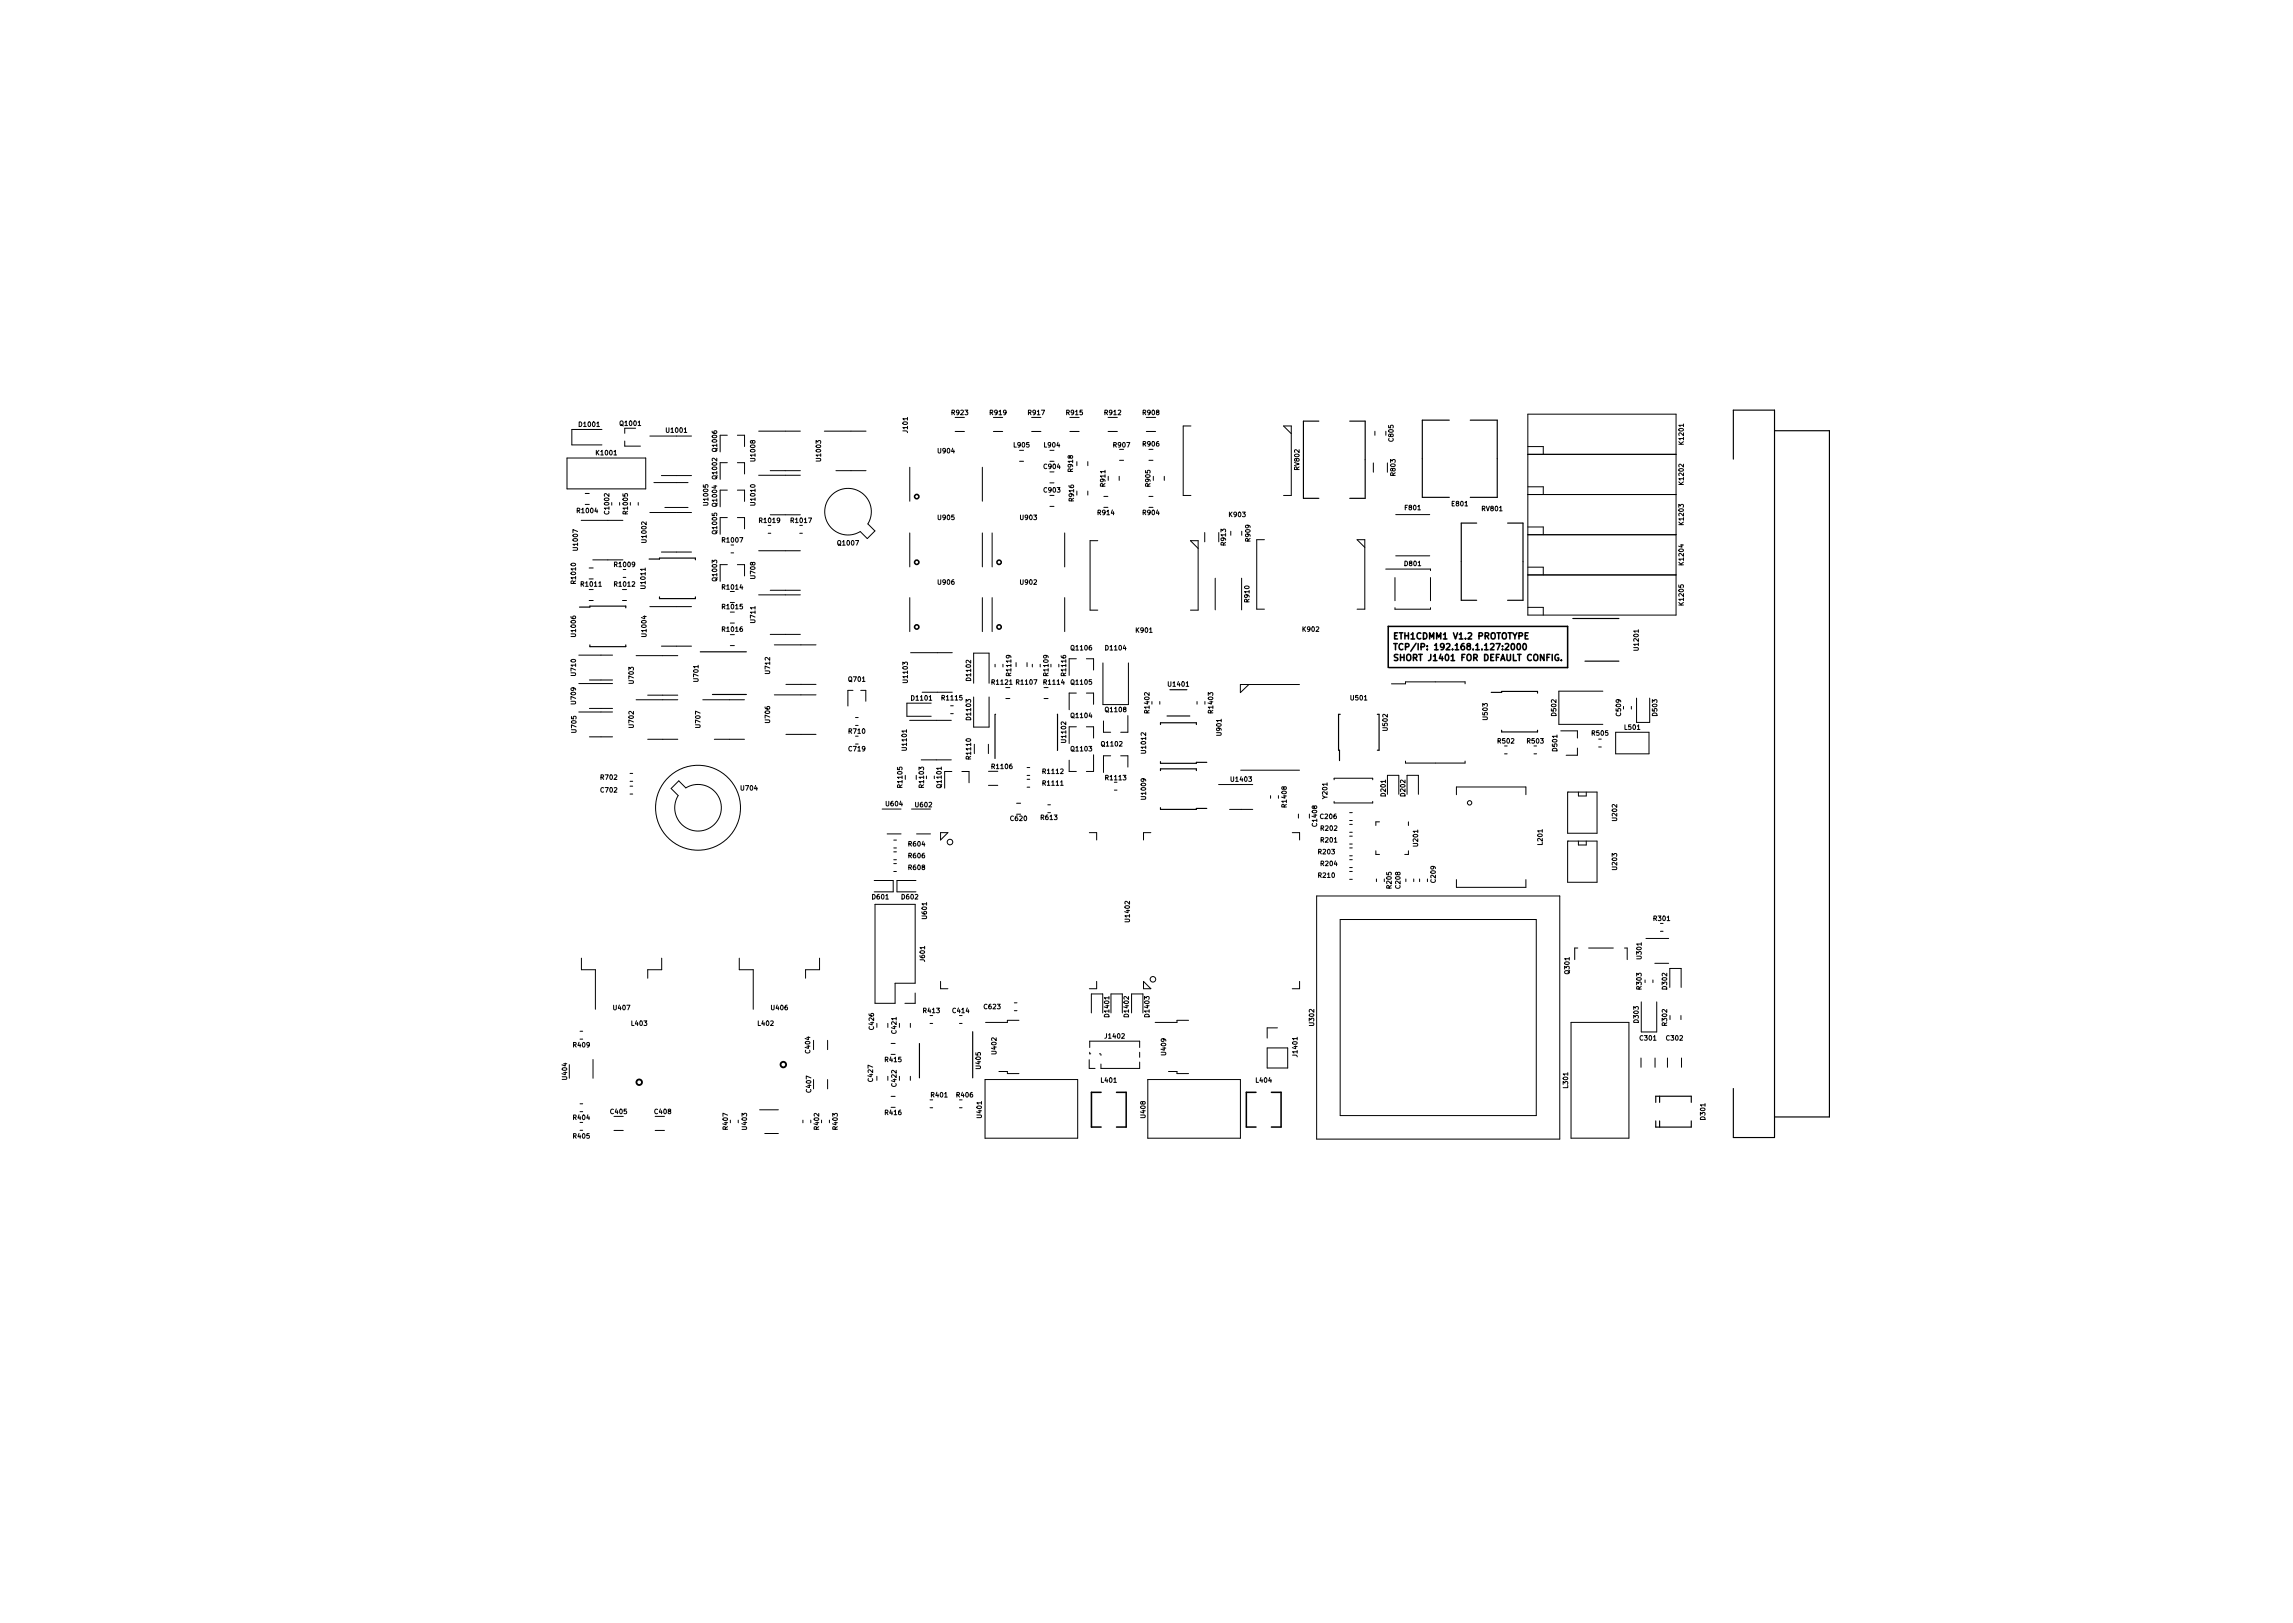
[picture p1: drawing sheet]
<svg xmlns="http://www.w3.org/2000/svg" width="297mm" height="210mm" viewBox="0 0 297 210" stroke-linecap="round" stroke-linejoin="round" font-family="sans-serif">
<defs><g id="words">
<g font-size="1.1">
<text x="180.3" y="82.8">ETH1CDMM1 V1.2 PROTOTYPE</text>
<text x="180.3" y="84.2">TCP/IP: 192.168.1.127:2000</text>
<text x="180.3" y="85.6">SHORT J1401 FOR DEFAULT CONFIG.</text>
</g>
<g font-size=".8">
<text x="123.3" y="53.8">R923</text>
<text x="128.3" y="53.8">R919</text>
<text x="133.2" y="53.8">R917</text>
<text x="138.2" y="53.8">R915</text>
<text x="143.1" y="53.8">R912</text>
<text x="148.1" y="53.8">R908</text>
<text x="75.1" y="55.3">D1001</text>
<text x="77.3" y="59">K1001</text>
<text x="80.4" y="55.2">Q1001</text>
<text x="86.4" y="56">U1001</text>
<text x="92.9" y="58.4" transform="rotate(-90 92.9 58.4)">Q1006</text>
<text x="97.8" y="59.6" transform="rotate(-90 97.8 59.6)">U1008</text>
<text x="106.3" y="59.6" transform="rotate(-90 106.3 59.6)">U1003</text>
<text x="117.6" y="56" transform="rotate(-90 117.6 56)">J101</text>
<text x="121.6" y="58.7">U904</text>
<text x="131.4" y="58">L905</text>
<text x="135.3" y="58">L904</text>
<text x="144.3" y="58">R907</text>
<text x="148.1" y="57.8">R906</text>
<text x="180.5" y="57.1" transform="rotate(-90 180.5 57.1)">C805</text>
<text x="218.1" y="57.5" transform="rotate(-90 218.1 57.5)">K1201</text>
<text x="91.7" y="65.4" transform="rotate(-90 91.7 65.4)">U1005</text>
<text x="92.9" y="65.5" transform="rotate(-90 92.9 65.5)">Q1004</text>
<text x="92.9" y="62" transform="rotate(-90 92.9 62)">Q1002</text>
<text x="97.8" y="65.4" transform="rotate(-90 97.8 65.4)">U1010</text>
<text x="135.3" y="60.7">C904</text>
<text x="135.3" y="63.8">C903</text>
<text x="139" y="61.1" transform="rotate(-90 139 61.1)">R918</text>
<text x="139.1" y="64.9" transform="rotate(-90 139.1 64.9)">R916</text>
<text x="143.2" y="63" transform="rotate(-90 143.2 63)">R911</text>
<text x="149" y="63" transform="rotate(-90 149 63)">R905</text>
<text x="168.3" y="60.8" transform="rotate(-90 168.3 60.8)">RV802</text>
<text x="180.8" y="61.6" transform="rotate(-90 180.8 61.6)">R803</text>
<text x="188.1" y="65.6">E801</text>
<text x="218.1" y="62.7" transform="rotate(-90 218.1 62.7)">K1202</text>
<text x="74.8" y="66.5">R1004</text>
<text x="74.8" y="71.2" transform="rotate(-90 74.8 71.2)">U1007</text>
<text x="78.9" y="66.5" transform="rotate(-90 78.9 66.5)">C1002</text>
<text x="81.3" y="66.5" transform="rotate(-90 81.3 66.5)">R1005</text>
<text x="83.7" y="70.2" transform="rotate(-90 83.7 70.2)">U1002</text>
<text x="92.9" y="69.1" transform="rotate(-90 92.9 69.1)">Q1005</text>
<text x="93.6" y="70.3">R1007</text>
<text x="98.5" y="67.7">R1019</text>
<text x="102.5" y="67.7">R1017</text>
<text x="108.6" y="70.7">Q1007</text>
<text x="121.6" y="67.4">U905</text>
<text x="132.2" y="67.4">U903</text>
<text x="142.3" y="66.7">R914</text>
<text x="148.1" y="66.7">R904</text>
<text x="158.8" y="70.6" transform="rotate(-90 158.8 70.6)">R913</text>
<text x="159.3" y="67">K903</text>
<text x="162" y="70.1" transform="rotate(-90 162 70.1)">R909</text>
<text x="182.1" y="66.1">F801</text>
<text x="192" y="66.2">RV801</text>
<text x="218.1" y="67.9" transform="rotate(-90 218.1 67.9)">K1203</text>
<text x="74.6" y="75.5" transform="rotate(-90 74.6 75.5)">R1010</text>
<text x="75.4" y="76">R1011</text>
<text x="79.7" y="76">R1012</text>
<text x="79.7" y="73.4">R1009</text>
<text x="83.6" y="76.2" transform="rotate(-90 83.6 76.2)">U1011</text>
<text x="92.9" y="75.2" transform="rotate(-90 92.9 75.2)">Q1003</text>
<text x="93.6" y="76.4">R1014</text>
<text x="97.8" y="74.9" transform="rotate(-90 97.8 74.9)">U708</text>
<text x="121.6" y="75.7">U906</text>
<text x="132.2" y="75.7">U902</text>
<text x="161.8" y="78" transform="rotate(-90 161.8 78)">R910</text>
<text x="182" y="73.3">D801</text>
<text x="218.1" y="73.1" transform="rotate(-90 218.1 73.1)">K1204</text>
<text x="74.6" y="82.4" transform="rotate(-90 74.6 82.4)">U1006</text>
<text x="83.7" y="82.4" transform="rotate(-90 83.7 82.4)">U1004</text>
<text x="93.6" y="81.8">R1016</text>
<text x="93.6" y="78.9">R1015</text>
<text x="97.8" y="80.6" transform="rotate(-90 97.8 80.6)">U711</text>
<text x="147.2" y="82">K901</text>
<text x="168.8" y="81.8">K902</text>
<text x="218.1" y="78.3" transform="rotate(-90 218.1 78.3)">K1205</text>
<text x="74.6" y="87.5" transform="rotate(-90 74.6 87.5)">U710</text>
<text x="82.1" y="88.5" transform="rotate(-90 82.1 88.5)">U703</text>
<text x="90.5" y="88.2" transform="rotate(-90 90.5 88.2)">U701</text>
<text x="99.7" y="87.2" transform="rotate(-90 99.7 87.2)">U712</text>
<text x="110" y="88.3">Q701</text>
<text x="117.6" y="88.3" transform="rotate(-90 117.6 88.3)">U1103</text>
<text x="125.8" y="88.1" transform="rotate(-90 125.8 88.1)">D1102</text>
<text x="128.6" y="88.7">R1121</text>
<text x="131" y="87.5" transform="rotate(-90 131 87.5)">R1119</text>
<text x="131.7" y="88.7">R1107</text>
<text x="135.3" y="88.7">R1114</text>
<text x="135.8" y="87.5" transform="rotate(-90 135.8 87.5)">R1109</text>
<text x="138.1" y="87.5" transform="rotate(-90 138.1 87.5)">R1116</text>
<text x="138.8" y="84.2">Q1106</text>
<text x="138.8" y="88.7">Q1105</text>
<text x="143.3" y="84.2">D1104</text>
<text x="151.4" y="88.9">U1401</text>
<text x="212.3" y="84.2" transform="rotate(-90 212.3 84.2)">U1201</text>
<text x="74.6" y="91.2" transform="rotate(-90 74.6 91.2)">U709</text>
<text x="74.7" y="94.8" transform="rotate(-90 74.7 94.8)">U705</text>
<text x="82.1" y="94.2" transform="rotate(-90 82.1 94.2)">U702</text>
<text x="90.7" y="94.2" transform="rotate(-90 90.7 94.2)">U707</text>
<text x="99.7" y="93.6" transform="rotate(-90 99.7 93.6)">U706</text>
<text x="110" y="95">R710</text>
<text x="118.1" y="90.7">D1101</text>
<text x="122.1" y="90.7">R1115</text>
<text x="125.8" y="93.2" transform="rotate(-90 125.8 93.2)">D1103</text>
<text x="138.8" y="93">Q1104</text>
<text x="143.3" y="92.2">Q1108</text>
<text x="148.9" y="92.3" transform="rotate(-90 148.9 92.3)">R1402</text>
<text x="157.1" y="92.3" transform="rotate(-90 157.1 92.3)">R1403</text>
<text x="158.2" y="95.2" transform="rotate(-90 158.2 95.2)">U901</text>
<text x="175" y="90.7">U501</text>
<text x="179.8" y="94.6" transform="rotate(-90 179.8 94.6)">U502</text>
<text x="192.7" y="93.2" transform="rotate(-90 192.7 93.2)">U503</text>
<text x="201.6" y="92.7" transform="rotate(-90 201.6 92.7)">D502</text>
<text x="206.3" y="95.3">R505</text>
<text x="210" y="92.7" transform="rotate(-90 210 92.7)">C509</text>
<text x="210.5" y="94.5">L501</text>
<text x="214.7" y="92.7" transform="rotate(-90 214.7 92.7)">D503</text>
<text x="77.9" y="101">R702</text>
<text x="110" y="97.3">C719</text>
<text x="116.9" y="101.9" transform="rotate(-90 116.9 101.9)">R1105</text>
<text x="117.5" y="97.1" transform="rotate(-90 117.5 97.1)">U1101</text>
<text x="119.7" y="101.9" transform="rotate(-90 119.7 101.9)">R1103</text>
<text x="122" y="102" transform="rotate(-90 122 102)">Q1101</text>
<text x="125.8" y="98.3" transform="rotate(-90 125.8 98.3)">R1110</text>
<text x="128.6" y="99.6">R1106</text>
<text x="135.2" y="100.2">R1112</text>
<text x="135.2" y="101.8">R1111</text>
<text x="138.1" y="96.1" transform="rotate(-90 138.1 96.1)">U1102</text>
<text x="138.8" y="97.3">Q1103</text>
<text x="142.8" y="96.7">Q1102</text>
<text x="143.3" y="101.1">R1113</text>
<text x="148.4" y="97.5" transform="rotate(-90 148.4 97.5)">U1012</text>
<text x="159.6" y="101.3">U1403</text>
<text x="194.1" y="96.3">R502</text>
<text x="197.9" y="96.3">R503</text>
<text x="201.7" y="97.3" transform="rotate(-90 201.7 97.3)">D501</text>
<text x="77.9" y="102.7">C702</text>
<text x="96" y="102.4">U704</text>
<text x="114.8" y="104.4">U604</text>
<text x="118.6" y="104.6">U602</text>
<text x="131" y="106.3">C620</text>
<text x="134.9" y="106.2">R613</text>
<text x="148.4" y="103.5" transform="rotate(-90 148.4 103.5)">U1009</text>
<text x="166.7" y="104.5" transform="rotate(-90 166.7 104.5)">R1408</text>
<text x="170.6" y="107" transform="rotate(-90 170.6 107)">C1408</text>
<text x="171.1" y="106.1">C206</text>
<text x="171.1" y="107.6">R202</text>
<text x="171.9" y="103.4" transform="rotate(-90 171.9 103.4)">Y201</text>
<text x="179.5" y="103.1" transform="rotate(-90 179.5 103.1)">D201</text>
<text x="182" y="103.1" transform="rotate(-90 182 103.1)">D202</text>
<text x="209.5" y="106.3" transform="rotate(-90 209.5 106.3)">U202</text>
<text x="117.7" y="112.7">R608</text>
<text x="117.7" y="111.2">R606</text>
<text x="117.7" y="109.6">R604</text>
<text x="170.8" y="113.7">R210</text>
<text x="170.8" y="110.7">R203</text>
<text x="171.1" y="112.2">R204</text>
<text x="171.1" y="109.1">R201</text>
<text x="183.7" y="109.6" transform="rotate(-90 183.7 109.6)">U201</text>
<text x="199.8" y="109.4" transform="rotate(-90 199.8 109.4)">L201</text>
<text x="209.5" y="112.6" transform="rotate(-90 209.5 112.6)">U203</text>
<text x="113" y="116.5">D601</text>
<text x="116.9" y="116.5">D602</text>
<text x="120.1" y="119" transform="rotate(-90 120.1 119)">U601</text>
<text x="146.3" y="119.3" transform="rotate(-90 146.3 119.3)">U1402</text>
<text x="180.3" y="115" transform="rotate(-90 180.3 115)">R205</text>
<text x="181.4" y="115" transform="rotate(-90 181.4 115)">C208</text>
<text x="186" y="114.3" transform="rotate(-90 186 114.3)">C209</text>
<text x="214.3" y="119.3">R301</text>
<text x="119.8" y="124.5" transform="rotate(-90 119.8 124.5)">J601</text>
<text x="212.6" y="124.2" transform="rotate(-90 212.6 124.2)">U301</text>
<text x="79.5" y="130.9">U407</text>
<text x="100" y="130.9">U406</text>
<text x="119.7" y="131.2">R413</text>
<text x="123.5" y="131.2">C414</text>
<text x="127.5" y="130.7">C623</text>
<text x="143.7" y="131.7" transform="rotate(-90 143.7 131.7)">D1401</text>
<text x="146.2" y="131.7" transform="rotate(-90 146.2 131.7)">D1402</text>
<text x="148.9" y="131.7" transform="rotate(-90 148.9 131.7)">D1403</text>
<text x="203.3" y="126.1" transform="rotate(-90 203.3 126.1)">Q301</text>
<text x="212.6" y="128.1" transform="rotate(-90 212.6 128.1)">R303</text>
<text x="215.9" y="128.1" transform="rotate(-90 215.9 128.1)">D302</text>
<text x="74.3" y="135.7">R409</text>
<text x="81.9" y="132.9">L403</text>
<text x="98.2" y="132.9">L402</text>
<text x="104.9" y="136.4" transform="rotate(-90 104.9 136.4)">C404</text>
<text x="113.2" y="133.3" transform="rotate(-90 113.2 133.3)">C426</text>
<text x="114.7" y="137.6">R415</text>
<text x="116.1" y="133.8" transform="rotate(-90 116.1 133.8)">C421</text>
<text x="129.1" y="136.5" transform="rotate(-90 129.1 136.5)">U402</text>
<text x="143.2" y="134.5">J1402</text>
<text x="151" y="136.6" transform="rotate(-90 151 136.6)">U409</text>
<text x="168.1" y="136.8" transform="rotate(-90 168.1 136.8)">J1401</text>
<text x="170.2" y="132.8" transform="rotate(-90 170.2 132.8)">U302</text>
<text x="212.3" y="132.4" transform="rotate(-90 212.3 132.4)">D303</text>
<text x="212.5" y="134.8">C301</text>
<text x="215.9" y="134.8">C302</text>
<text x="215.9" y="132.8" transform="rotate(-90 215.9 132.8)">R302</text>
<text x="73.5" y="139.8" transform="rotate(-90 73.5 139.8)">U404</text>
<text x="105.1" y="141.5" transform="rotate(-90 105.1 141.5)">C407</text>
<text x="113.1" y="140.1" transform="rotate(-90 113.1 140.1)">C427</text>
<text x="116.1" y="140.7" transform="rotate(-90 116.1 140.7)">C422</text>
<text x="120.7" y="142.2">R401</text>
<text x="124" y="142.2">R406</text>
<text x="127" y="138.4" transform="rotate(-90 127 138.4)">U405</text>
<text x="142.7" y="140.2">L401</text>
<text x="162.8" y="140.2">L404</text>
<text x="203.1" y="140.9" transform="rotate(-90 203.1 140.9)">L301</text>
<text x="74.3" y="147.5">R405</text>
<text x="74.3" y="145.1">R404</text>
<text x="79.1" y="144.3">C405</text>
<text x="84.9" y="144.3">C408</text>
<text x="94.3" y="146.3" transform="rotate(-90 94.3 146.3)">R407</text>
<text x="96.8" y="146.3" transform="rotate(-90 96.8 146.3)">U403</text>
<text x="106.1" y="146.3" transform="rotate(-90 106.1 146.3)">R402</text>
<text x="108.5" y="146.3" transform="rotate(-90 108.5 146.3)">R403</text>
<text x="114.7" y="144.4">R416</text>
<text x="127.2" y="144.8" transform="rotate(-90 127.2 144.8)">U401</text>
<text x="148.4" y="144.8" transform="rotate(-90 148.4 144.8)">U408</text>
<text x="220.9" y="145" transform="rotate(-90 220.9 145)">D301</text>
</g>
</g></defs>
<g fill="none" stroke="#000" stroke-width=".2">
<path d="M179.8 86.5v-5.4h23.3v5.4h-23.1M195 83.5l.3-.1 .1 .2-.5 .6h.5M195.8 83.5l.1-.1a.43 .43 0 0 1 .3 .4 .43 .43 0 0 1-.3 .4l-.2-.3zM196.6 83.5l.1-.1a.43 .43 0 0 1 .3 .4 .43 .43 0 0 1-.3 .4l-.2-.3zM197.4 83.4h.1a.43 .43 0 0 1 .2 .4 .43 .43 0 0 1-.2 .4 .53 .53 0 0 1-.1-.8zM197.6 82.4h.2M198 82h-.4v.8h.4M201.9 84.8a.36 .36 0 0 0-.5 .4 .36 .36 0 0 0 .5 .3v-.3h-.1M202.3 85.5v.1M142.6 141.5h-1.2v4.5h1.2M144.6 141.5h1.3v4.5h-1.3M162.7 141.5h-1.2v4.5h1.2"/>
<path d="M164.7 141.5h1.3v4.5h-1.3"/>
<circle cx="118.8" cy="64.3" r=".28"/>
<circle cx="118.8" cy="72.8" r=".28"/>
<circle cx="129.4" cy="72.8" r=".28"/>
<circle cx="118.8" cy="81.2" r=".28"/>
<circle cx="129.4" cy="81.2" r=".28"/>
</g>
<g fill="none" stroke="#000" stroke-width=".13">
<path d="M73.4 59.3h10.2v4h-10.2zM78 55.6h-3.9v2h3.9M80.9 57.1v.7h2.1M82.3 55.5h-1.4v.6M84.2 56.5h5.4M94.2 56.4h-.9v2.1M94.2 59.9h-.9v2.2M95.5 56.4h.9v1.4M95.5 59.9h.9v1.5M98.3 55.9h5.4M106.8 55.9h5.4M123.7 54.1h1.2"/>
<path d="M123.7 55.9h1.2M128.7 54.1h1.2M128.7 55.9h1.2M132.1 58.3h.5M132.1 59.8h.5M133.6 54.1h1.2M133.6 55.9h1.2M136 58.3h.5M136 59.8h.5M138.6 54.1h1.2M138.6 55.9h1.2M139.5 59.8v.5"/>
<path d="M140.9 59.8v.5M143.5 54.1h1.2M143.5 55.9h1.2M145 59.6h.5M148.5 54.1h1.2M148.5 55.9h1.2M148.8 59.6h.6M148.8 58.2h.6M154.3 55.2h-1v9h1M167.3 56.2l-1-1h1v9h-1M177.9 60v1.2M178.1 55.9v.5"/>
<path d="M179.5 55.9v.5M179.7 60v1.2M197.9 57.9h2v1M197.9 53.7h19.2v26h-19.2zM197.9 58.9h19.2M75.3 67.4h5.4M75.8 65.3h.5M75.8 63.9h.5M76.3 73.6h.5M76.3 75h.5M76.3 77.8h.5M76.3 76.4h.5"/>
<path d="M76.8 72.5h3.9M79.2 65.1v.3M80.3 65.1v.3M80.6 77.8h.6M80.6 76.4h.6M80.7 74.8h.4M80.7 73.8h.4M81.7 65.1v.3M82.7 65.1v.3M84.2 78.6h5.4M84.2 66.4h5.4M84.7 62.5h4.4"/>
<path d="M85.7 71.5h3.9M85.7 61.6h3.9M86.1 65.7h3M94.2 63.5h-.9v2.2M94.2 67.1h-.9v2.1M94.2 73.1h-.9v2.2M94.6 79.3h.5M94.7 71.6h.3M94.7 70.6h.3M95.5 63.5h.9v1.5M95.5 67.1h.9v1.4M95.5 73.1h.9v1.5"/>
<path d="M98.3 61.6h5.4M98.3 77.1h5.4M98.3 71.3h5.4M99.5 69.1h.4M99.5 68.1h.4M99.8 66.7h3.9M99.8 61h3.9M99.8 76.5h3.9M103.6 69.1h.3M103.6 68.1h.3M108.3 61h3.9M111.4 68.9l.9 .9 1-1-.9-.9a3 3 0 0 0-2-4.6 3 3 0 0 0-3.5 3.5 3 3 0 0 0 4.5 2.1"/>
<path d="M117.9 60.5v4.4M117.9 69v4.4M117.9 77.4v4.4M127.3 60.5v4.4M127.3 69v4.4M127.3 77.4v4.4M128.5 69v4.4M128.5 77.4v4.4M136 61.1h.5M136 62.6h.5M136 64.2h.5M136 65.6h.5"/>
<path d="M137.9 69v4.4M137.9 77.4v4.4M139.5 63.6v.5M140.9 63.6v.5M142.2 70h-1v9h1M143 65.7h.5M143 64.3h.5M143.6 61.7v.5M145 61.7v.5M148.8 65.7h.6M148.8 64.3h.6M149.4 61.7v.5"/>
<path d="M150.8 61.7v.5M155.2 71l-1-1h1v9h-1M156.1 69v1.2M157.4 74.9v4.1M157.9 69v1.2M159.4 68.8v.5M160.8 74.9v4.1M160.9 68.8v.5M163.8 69.9h-1v9h1M176.8 70.9l-1-1h1v9h-1M179.5 73.7h5.8v.2M180.7 78.7v.2h4.6v-.2"/>
<path d="M180.7 74.8v3M180.8 66.7h4.4M180.8 72h4.4M185.3 74.8v3M197.9 63.1h2v1M197.9 68.3h2v1M197.9 73.5h2v1M197.9 78.7h2v1M197.9 74.5h19.2M197.9 69.3h19.2M197.9 64.1h19.2M75 88.6h4.4"/>
<path d="M75 92.2h4.4M75 84.9h4.4M76.4 91.8h3M76.4 95.5h3M76.4 88.1h3M82.4 90.7h5.4M82.4 84.9h5.4M83.9 95.8h3.9M83.9 90.1h3.9M85.7 83.7h3.9M91 90.7h5.4M92.5 95.8h3.9"/>
<path d="M94.6 83.6h.5M94.6 82.2h.5M94.6 80.7h.5M99.8 82.2h3.9M100.3 83.5h5.4M100.3 90h5.4M101.8 88.7h3.9M101.8 95.1h3.9M110.5 89.4h-.7v2.1M110.8 94h.4M110.8 93h.4M110.8 95.4h.4"/>
<path d="M110.8 96.4h.4M111.5 89.4h.7v1.4M117.8 93.3h5.4M118 84.6h5.4M119.3 98.4h3.9M119.5 89.7h3.9M120.6 91.1h-3.1v1.7h3.1M123.1 92.5h.4M123.1 91.4h.4M123.3 99.9h-.9v2.2M124.6 99.9h.9v1.5M126.1 88.5v-3.9h2v3.9"/>
<path d="M126.1 90.3v3.9h2v-3.9M126.2 96.4v1.2M128 96.4v1.2M128 99.9h1.3M128.9 86.1v.3M129.9 86.1v.3M130.3 90.5h.5M130.3 89.1h.5M131.6 85.8v.6M133 85.8v.6M133.1 99.4h.3M133.7 86.1v.3"/>
<path d="M134.7 86.1v.3M135.2 90.5h.6M135.2 89.1h.6M136.1 86.1v.3M137.2 86.1v.3M138.5 98.5v1.4h.9M139.4 85.3h-.9v2.2M139.4 89.8h-.9v2.1M139.4 94.2h-.9v2.1M140.7 85.3h1v1.5M140.7 89.8h1v1.4M140.7 94.2h1v1.4"/>
<path d="M141.7 97.8v2.1h-1M142.9 85.9v5.4h3.3v-5.4M142.9 93.4v1.5h1M143.9 97.9h-1v2.2M145.2 97.9h.9v1.5M146.1 92.7v2.2h-.9M149.2 90.9v.3M150.2 90.9v.3M155.1 90.9v.3M156.1 90.9v.3M160.7 99.8h7.6M161.8 88.7l-1.1 1v-1h7.6"/>
<path d="M180.3 88.6h1.8v-.3h7.7v.3M182.1 98.6v.3h7.7v-.3M194.9 97.7h.3M194.9 96.6h.3M198.7 97.7h.4M198.7 96.6h.4M202.2 94.7h2.1v.9M204.3 96.9v.9h-1.4M207.1 95.8h.3M207.1 96.8h.3M207.6 89.5h-5.7v4.3h5.7M209.3 94.9h4.3v2.8h-4.3z"/>
<path d="M210.3 91.5v.4M211.3 91.5v.4M212 90.4v3.2h1.7v-3.2M81.6 101.2h.4M81.6 100.2h.4M81.6 102.9h.4M81.6 101.8h.4M86.9 102.1l1-.9 .9 .9a3 3 0 0 1 4.6 2 3 3 0 0 1-3.5 3.5 3 3 0 0 1-2-4.5zM113.2 114.1h2.5v1.4h-2.5M113.4 117.2h5.2v10.2h-2.6v2.6h-2.6zM114.3 104.8h2.4M114.9 108h1.8"/>
<path d="M115.8 111.9h.3M115.8 112.9h.3M115.8 110.4h.3M115.8 111.4h.3M115.8 108.8h.3M115.8 109.9h.3M117.3 100.4v.6M118.1 104.8h2.4M118.7 114.1h-2.5v1.4h2.5M118.7 100.4v.6M118.7 108h1.8M120 100.5v.4"/>
<path d="M121 100.5v.4M121.8 107.9h1l-1 .9zM128 101.7h1.3M131.7 104.1h.5M133.1 100.5h.3M133.1 102h.3M133.1 101h.3M135.7 105.3h.4M135.7 104.3h.4M141.1 107.9h1v.9M144.4 102.4h.3M149.1 107.9h-1v.9"/>
<path d="M157.9 101.6h4.4M159.3 104.9h3M164.6 103.1v.3M165.6 103.1v.3M167.4 107.9h1v.9M168.2 105.5v.5M169.6 105.5v.5M170.6 116.1h31.5v31.5h-31.5zM172.8 101v-.2h5v.2M172.8 103.8v.2h5v-.2M173.6 119.1h25.4v25.4h-25.4zM174.8 105.3h.4"/>
<path d="M174.8 112.9h.4M174.8 111.4h.4M174.8 109.8h.4M174.8 113.9h.4M174.8 112.4h.4M174.8 110.9h.4M174.8 106.8h.4M174.8 107.8h.4M174.8 108.3h.4M174.8 109.3h.4M174.8 106.3h.4M178.2 110.2v.5h.5"/>
<path d="M178.3 113.9v.3M178.7 106.5h-.5v.4M179.3 113.9v.3M179.7 102.9v-2.5h1.5v2.5M182.1 113.9v.3M182.3 102.9v-2.5h1.4v2.5M182.4 106.5v.4M182.4 110.2v.5h-.4M183.1 113.9v.3M183.9 113.9v.3M184.9 113.9v.3M188.7 103v-1h9v1"/>
<path d="M188.7 114v1h9v-1M203.1 109h3.8v5.3h-3.8zM203.1 102.6h3.8v5.3h-3.8zM204.5 102.6v.5h1v-.5M204.5 109v.5h1v-.5M215.1 119.6h.3M73.8 137.9v1.8M75.1 133.6h.4M75.1 134.6h.4M75.3 124.1v1.5h1.8v5.2M76.8 137.3v2.4M85.7 124.1v1.5h-1.8v1.1"/>
<path d="M95.8 124.1v1.5h1.8v5.2M105.4 134.8v1.2M105.4 139.9v1.2M106.2 124.1v1.5h-1.8v1.1M107.2 134.8v1.2M107.2 139.9v1.2M113.6 132.6v.5M113.6 139.4v.6M115 132.6v.5M115 139.4v.6M115.4 136.6h.6M115.4 135.2h.6"/>
<path d="M116.5 132.6v.5M116.5 139.4v.6M117.9 132.6v.5M117.9 139.4v.6M118.6 128.6v1.4h-1.4M120.5 131.6h.3M120.5 132.6h.3M121.8 127.1v1h1M124.3 131.6h.3M124.3 132.6h.3M127.6 139.9h12v7.6h-12zM129.4 138.8h1.1v.3h1.5"/>
<path d="M131.4 129.9h.3M131.4 130.9h.3M132 132.2h-1.5v.3h-2.8M141.1 137.3v1.1h.8M141.2 135.7v-.8h6.4v.8M141.2 136.3v.2h.1M141.4 131.2v-2.4h1.4v2.4M142.1 127.1v1h-1M142.4 136.5h.2M142.6 136.6v.1M143.9 131.2v-2.4h1.5v2.4M146.6 131.2v-2.4h1.5v2.4"/>
<path d="M147.6 137.6v.8h-5v-.6M147.6 136.3v.7M148.1 127.1l1 1h-1zM148.7 139.9h12v7.6h-12zM151.4 138.8h1.1v.3h1.5M154 132.2h-1.5v.3h-2.9M164.2 135.8h2.6v2.6h-2.6zM165.5 133.2h-1.3v1.3M168.4 127.1v1h-1M203.5 132.4h7.5v15h-7.5zM204.4 122.8h-.4v1.5M205.8 122.8h3.2"/>
<path d="M210.4 122.8h.4v1.5M212.6 137.1v1.2M212.6 129.8v3.9h2v-3.9M213.1 127v.3M213.2 121.6h3M214.1 127v.3M214.4 124.8h1.8M214.4 137.1v1.2M215.1 120.6h.3M216 137.1v1.2M216.3 127.9v-2.4h1.5v2.4M216.3 131.6v.5"/>
<path d="M217.8 131.6v.5M217.8 137.1v1.2M75.1 146.4h.4M75.1 145.4h.4M75.1 143h.4M75.1 144h.4M79.5 146.4h1.2M79.5 144.6h1.2M84.9 146.4h1.2M84.9 144.6h1.2M94.6 145.1v.4M95.6 145.1v.4"/>
<path d="M98.4 143.8h2.4M99.1 146.8h1.7M104 145.1v.4M105 145.1v.4M106.4 145.1v.4M107.4 145.1v.4M115.4 143.5h.6M115.4 142h.6M120.5 142.5h.3M120.5 143.5h.3M124.3 142.5h.3M124.3 143.5h.3"/>
<circle cx="90.4" cy="104.6" r="5.5"/>
<circle cx="123.1" cy="109.1" r=".36"/>
<circle cx="190.4" cy="104" r=".28"/>
<circle cx="149.4" cy="126.9" r=".36"/>
</g>
<g fill="none" stroke="#000" stroke-width=".15">
<path d="M170.8 54.6h-2v10h2M174.8 54.6h2v10h-2M187.7 54.4h-3.5v10h3.5M190.5 54.4h3.5v10h-3.5M224.5 59.5v-6.4h5.4v94.3h-5.4v-6.4M229.9 55.8h7.1v88.9h-7.1M75.1 78.6h1.3v-.1h4.7v.2M84.1 72.4h1.3v-.1h4.7v.2M85.4 77.3v.2h4.7v-.2M191.3 67.8h-2v10h2M195.3 67.8h2v10h-2M76.4 83.5v.3h4.7v-.3"/>
<path d="M90.7 84.4h6M92.3 90h4.4M128.9 92.5v5.8M128.9 92.5h.1M137 92.5v4.7M150.3 98.7v.2h4.7v-.1h1.3M150.3 93.9v-.3h4.7v.3M150.3 99.8v-.2h4.7v.2M151.2 92.8h2.9M151.6 89.4h2.2M173.6 92.5h-.2v4.7h.1v1.3M178.4 92.5h.2v4.7h-.2"/>
<path d="M193.2 89.7h1.3v-.1h4.7v.2M194.5 94.6v.2h4.7v-.2M203.7 80.1h6M205.3 85.7h4.4M150.3 104.6v.3h4.7v-.2h1.3M119.1 135.2v4.4M126 133.7v5.9M214.5 142.8v-.8h4.6v.8M214.5 145.2v.8h4.6v-.8M215 142v.8M215 145.2v.8"/>
</g>
<g fill="none" stroke="#000" stroke-width=".24">
<circle cx="101.5" cy="137.9" r=".36"/>
<circle cx="82.8" cy="140.2" r=".36"/>
</g>
<use href="#words"/>
</svg>
